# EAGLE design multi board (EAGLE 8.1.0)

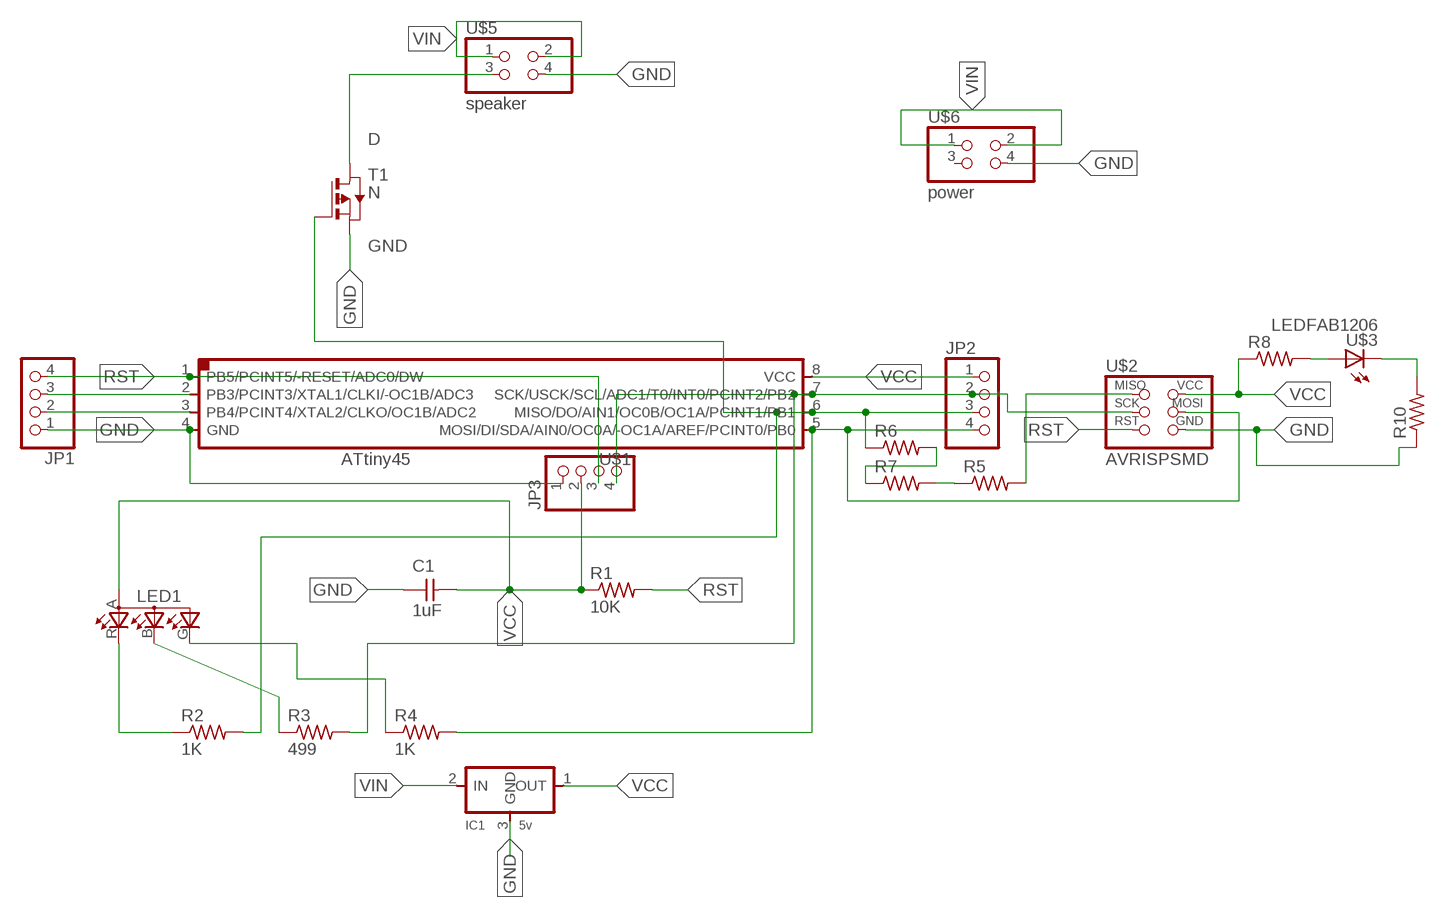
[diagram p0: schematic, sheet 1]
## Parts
C1  1uF  CAP-UNPOLARIZEDFAB  [C1206FAB]
IC1  5v  REGULATORSOT23  [SOT23]
JP1  PINHD-1X4  [1X04]
JP2  PINHD-1X4  [1X04]
JP3  PINHD-1X4  [1X04]
LED1  LEDRGBOLD  [P-LCC-4-3]
R1  10K  RES-US1206FAB  [R1206FAB]
R2  1K  RES-US1206FAB  [R1206FAB]
R3  499  RES-US1206FAB  [R1206FAB]
R4  1K  RES-US1206FAB  [R1206FAB]
R5  RES-US1206FAB  [R1206FAB]
R6  RES-US1206FAB  [R1206FAB]
R7  RES-US1206FAB  [R1206FAB]
R8  RES-US1206FAB  [R1206FAB]
R10  RES-US1206FAB  [R1206FAB]
T1  N  PMOSFETSOT23  [SOT-23]
U$1  ATTINY45SI  [SOIC8]
U$2  AVRISPSMD  [2X03SMD]
U$3  LEDFAB1206  [LED1206FAB]
U$5  speaker  PINHD-2X2-SMD  [2X02SMD]
U$6  power  PINHD-2X2-SMD  [2X02SMD]

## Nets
D: T1.1(D) U$5.3
GND: C1.1 IC1.3(GND) JP1.1 JP3.1 R10.1 T1.2(S) U$1.4(GND) U$2.6(GND) U$5.4 U$6.4
N$1: JP2.4 R4.2 U$1.5(MOSI/DI/SDA/AIN0/OC0A/-OC1A/AREF/PCINT0/PB0) U$2.4(MOSI)
N$2: JP2.2 JP3.4 R3.2 U$1.7(SCK/USCK/SCL/ADC1/T0/INT0/PCINT2/PB2) U$2.3(SCK)
N$3: JP1.3 U$1.2(PB3/PCINT3/XTAL1/CLKI/-OC1B/ADC3)
N$4: R5.2 U$2.1(MISO)
N$5: JP1.2 U$1.3(PB4/PCINT4/XTAL2/CLKO/OC1B/ADC2)
N$6: LED1.R(CRED) R2.1
N$7: JP2.3 R2.2 R6.1 T1.3(G) U$1.6(MISO/DO/AIN1/OC0B/OC1A/PCINT1/PB1)
N$8: LED1.B(CBLUE) R3.1
N$9: R5.1 R7.2
N$10: LED1.G(CGREEN) R4.1
N$11: R6.2 R7.1
N$12: R8.2 U$3.1(A)
N$13: R10.2 U$3.2(C)
RST: JP1.4 JP3.3 R1.2 U$1.1(PB5/PCINT5/-RESET/ADC0/DW) U$2.5(RST)
VCC: C1.2 IC1.1(OUT) JP2.1 JP3.2 LED1.A(A2) R1.1 R8.1 U$1.8(VCC) U$2.2(VCC)
VIN: IC1.2(IN) U$5.1 U$5.2 U$6.1 U$6.2
Unconnected: U$6.3

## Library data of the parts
C1 = fab(1):CAP-UNPOLARIZED
IC1 = fab(1):REGULATOR
JP1-JP3 = pinhead:PINHD-1X4: PIN HEADER
LED1 = fab:LEDRGBOLD: OSRAM Hyper Multi TOPLED® Hyper-Bright LED LATB T686 Source: http://www.osram.convergy.de/
R1 = fab(1):RES-US: Resistor (US Symbol)
R2-R8 R10 = fab:RES-US: Resistor (US Symbol)
T1 = fab(1):PMOSFET: MOS FET
U$1 = fab(1):ATTINY45
U$2 = fab(1):AVRISP
U$3 = fab:LED: LED
U$5 U$6 = fab(1):PINHD-2X2-SMD

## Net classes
0 default: width 0.406 mm, drill 0.406 mm, clearance 0.406 mm

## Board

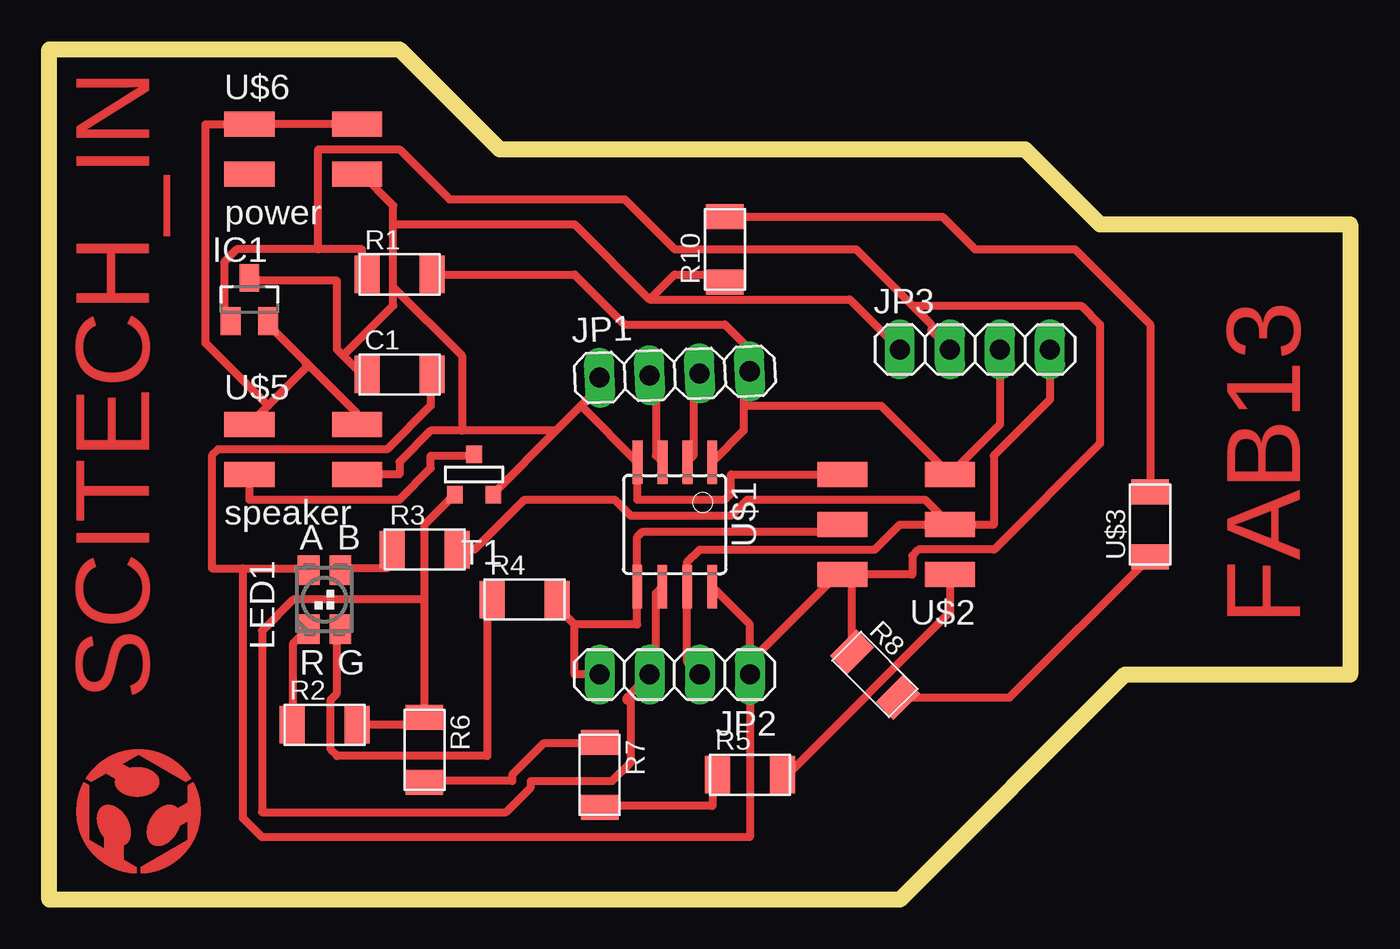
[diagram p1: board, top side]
Size 66.04 x 43.18 mm. Coordinates in mm from the lower left corner, seen from the top.
Outline: 0,43.18 17.78,43.18 22.86,38.1 49.53,38.1 53.34,34.29 66.04,34.29 66.04,11.43 54.61,11.43 43.18,0 0,0 0,43.18
Copper layers (1*16): Top 0.035mm / dielectric 1.5mm / Bottom 0.035mm
Design rules "default *": minimum track width 16mil, minimum drill 24mil, track to track 16mil, track to pad 16mil, pad to pad 16mil, via to via 16mil, smd to smd 16mil, copper to edge 40mil, drill to drill 8mil, minimum pad ring 10mil, minimum via ring 8mil, stop-mask expansion 4mil, vias tented up to drill 0mil, thermal gap 10mil

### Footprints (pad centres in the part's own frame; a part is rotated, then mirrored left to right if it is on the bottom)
C1206FAB = smd 1.27 x 1.905: 1 -1.651,0; 2 1.651,0
SOT23 = smd 1 x 1.4: 1 -0.95,-1.1; 2 0.95,-1.1; 3 0,1.1
1X04 = drill 1.016 long: 1 -3.81,0; 2 -1.27,0; 3 1.27,0; 4 3.81,0
P-LCC-4-3 = smd 1.1 x 1.5: A -0.8,1.5; B 0.8,1.5; G 0.8,-1.5; R -0.8,-1.5
R1206FAB = smd 1.27 x 1.905: 1 -1.651,0; 2 1.651,0
SOT-23 = smd 0.787 x 0.889: 1 0.025,-1.016; 2 -0.94,1.016; 3 0.991,1.016
SOIC8 = smd 0.5 x 2.2: 1 -1.905,-3.154; 2 -0.645,-3.154; 3 0.625,-3.154; 4 1.895,-3.154; 5 1.905,3.154; 6 0.635,3.154; 7 -0.635,3.154; 8 -1.905,3.154
2X03SMD = smd 2.54 x 1.27: 1 -2.54,2.54; 2 2.92,2.54; 3 -2.54,0; 4 2.92,0; 5 -2.54,-2.54; 6 2.92,-2.54
LED1206FAB = smd 1.27 x 1.905: 1 -1.651,0; 2 1.651,0
2X02SMD = smd 2.54 x 1.27: 1 -2.54,1.27; 2 2.92,1.27; 3 -2.54,-1.27; 4 2.92,-1.27

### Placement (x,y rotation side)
C1  17.78,26.67 0 top
IC1  10.16,30.48 0 top
JP1  31.75,26.67 2.4 top
JP2  31.75,11.43 180 top
JP3  46.99,27.94 0 top
LED1  13.97,15.24 0 top
R1  17.78,31.75 0 top
R2  13.97,8.89 0 top
R3  19.05,17.78 0 top
R4  24.13,15.24 0 top
R5  35.56,6.35 0 top
R6  19.05,7.62 270 top
R7  27.94,6.35 270 top
R8  41.91,11.43 315 top
R10  34.29,33.02 90 top
T1  21.59,21.59 180 top
U$1  31.75,19.05 180 top
U$2  43.18,19.05 180 top
U$3  55.88,19.05 90 top
U$5  12.7,22.86 0 top
U$6  12.7,38.1 0 top

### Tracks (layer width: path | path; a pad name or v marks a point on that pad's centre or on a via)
D
  Top 0.406: U$5.3 10.16,20.32 17.78,20.32 19.37,21.91 19.37,22.54 21.27,22.54 T1.1
GND
  Top 0.406: 26.99,25.08 27.94,26.04 27.94,26.35 JP1.1 | 26.99,25.08 25.72,23.81 | 25.72,23.81 22.54,20.64 T1.2 | 26.99,25.08 29.84,22.22 U$1.4 29.84,21.91 29.84,20.32 34.29,20.32 34.61,20.64 34.61,21.59 U$2.6 | U$5.4 17.78,21.59 17.78,22.22 19.37,23.81 20.95,23.81 | 25.72,23.81 20.95,23.81 | 14.92,27.62 15.88,26.67 C1.1 | 14.92,27.62 14.61,27.94 14.61,31.43 10.16,31.43 IC1.3 | 17.46,31.11 17.46,30.16 14.92,27.62 | 17.46,31.11 17.46,34.29 | 17.46,34.29 17.46,35.24 15.88,36.83 U$6.4 | 20.95,23.81 20.95,27.62 17.46,31.11 | 17.46,34.29 26.67,34.29 30.48,30.48 | 30.48,30.48 40.64,30.48 JP3.1 | 30.48,30.48 31.75,31.75 33.91,31.75 R10.1
N$1
  Top 0.406: JP2.4 26.67,11.43 26.67,13.97 | 25.4,14.86 R4.2 25.72,14.92 26.67,13.97 | 26.67,13.97 29.84,13.97 U$1.5 29.84,18.41 30.12,18.69 39.9,18.69 U$2.4
N$2
  Top 0.406: 33.02,10.16 JP2.2 32.38,12.06 U$1.7 32.38,17.14 33.02,17.78 41.91,17.78 43.18,19.05 U$2.3 | U$2.3 47.94,19.05 47.94,22.54 50.8,25.4 JP3.4 | U$2.3 44.45,20.32 35.44,20.32 34.63,19.51 29.51,19.51 28.7,20.32 24.13,20.32 21.59,17.78 R3.2
N$3
  Top 0.406: U$1.2 32.38,22.22 32.7,22.54 32.7,26.67 JP1.3
N$4
  Top 0.406: U$2.1 45.72,14.61 37.47,6.35 R5.2
N$5
  Top 0.406: U$1.3 31.11,22.22 30.8,22.54 30.8,26.35 JP1.2
N$6
  Top 0.406: LED1.R 13.02,13.65 12.38,13.02 12.38,8.89 R2.1
N$7
  Top 0.406: U$1.6 31.11,15.88 30.8,15.56 30.8,11.75 JP2.3 29.53,10.48 | 29.31,10.1 29.31,10.26 29.53,10.48 | 19.05,15.24 R6.1 19.05,8.89 R2.2 | 19.05,15.24 19.05,19.05 20.32,20.32 T1.3 | 29.53,10.48 29.53,6.98 28.57,6.03 24.45,6.03 24.45,5.71 23.18,4.45 10.79,4.45 10.79,13.65 12.38,15.24 19.05,15.24
N$8
  Top 0.406: LED1.B 14.92,16.83 17.14,16.83 17.14,17.78 R3.1
N$9
  Top 0.406: R7.2 27.94,4.76 33.66,4.76 33.66,6.35 R5.1
N$10
  Top 0.406: LED1.G 14.61,13.65 14.61,10.48 14.29,10.16 14.29,7.62 14.61,7.3 22.22,7.3 22.22,15.24 R4.1
N$11
  Top 0.406: R6.2 19.05,6.03 23.5,6.03 23.5,6.35 25.08,7.94 27.94,7.94 R7.1
N$12
  Top 0.406: U$3.1 48.74,10.26 R8.2
N$13
  Top 0.406: R10.2 45.34,34.67 46.99,33.02 52.07,33.02 55.88,29.21 U$3.2
RST
  Top 0.406: JP3.3 48.26,24.13 U$2.5 42.23,25.08 35.24,25.08 | JP1.4 35.24,26.99 | 35.24,25.08 35.24,26.67 JP1.4 | 35.24,25.08 35.24,23.81 33.66,22.22 U$1.1 | R1.2 26.67,31.75 29.21,29.21 34.29,29.21 35.56,27.94 JP1.4
VCC
  Top 0.406: 13.02,16.51 LED1.A 13.02,16.83 9.84,16.83 | 9.84,16.83 8.26,16.83 8.26,22.54 8.57,22.86 17.14,22.86 19.37,25.08 19.37,26.67 C1.2 | 35.56,12.06 35.56,13.97 33.66,15.88 U$1.8 | 35.56,12.06 40.01,16.51 U$2.2 | 35.56,12.06 JP2.1 35.56,3.17 10.79,3.17 9.84,4.13 9.84,16.83 | 13.65,33.02 15.88,33.02 15.88,31.75 R1.1 | 13.65,33.02 9.53,33.02 8.89,32.38 8.89,29.84 9.21,29.53 IC1.1 | JP3.2 44.77,28.89 44.77,29.21 43.82,30.16 | 13.65,33.02 13.65,38.1 17.78,38.1 20.32,35.56 29.21,35.56 31.75,33.02 40.96,33.02 43.82,30.16 | U$2.2 43.82,16.51 43.82,17.46 44.13,17.78 47.97,17.78 53.34,23.15 53.34,29.21 52.39,30.16 43.82,30.16 | U$2.2 40.74,16.51 | R8.1 40.74,16.03 U$2.2
VIN
  Top 0.406: U$5.2 15.56,24.13 15.56,24.77 13.02,27.3 | U$6.2 U$6.1 7.94,39.37 7.94,28.26 11.11,25.08 | 13.02,27.3 11.11,29.21 IC1.2 | 11.11,25.08 13.02,26.99 13.02,27.3 | 11.11,25.08 U$5.1
(copper drawn outside any net)
  shapes: Top area x3420

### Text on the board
Top: FAB13 | SCITECH_IN | /home/scitechindian/eagle/logo.bmp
